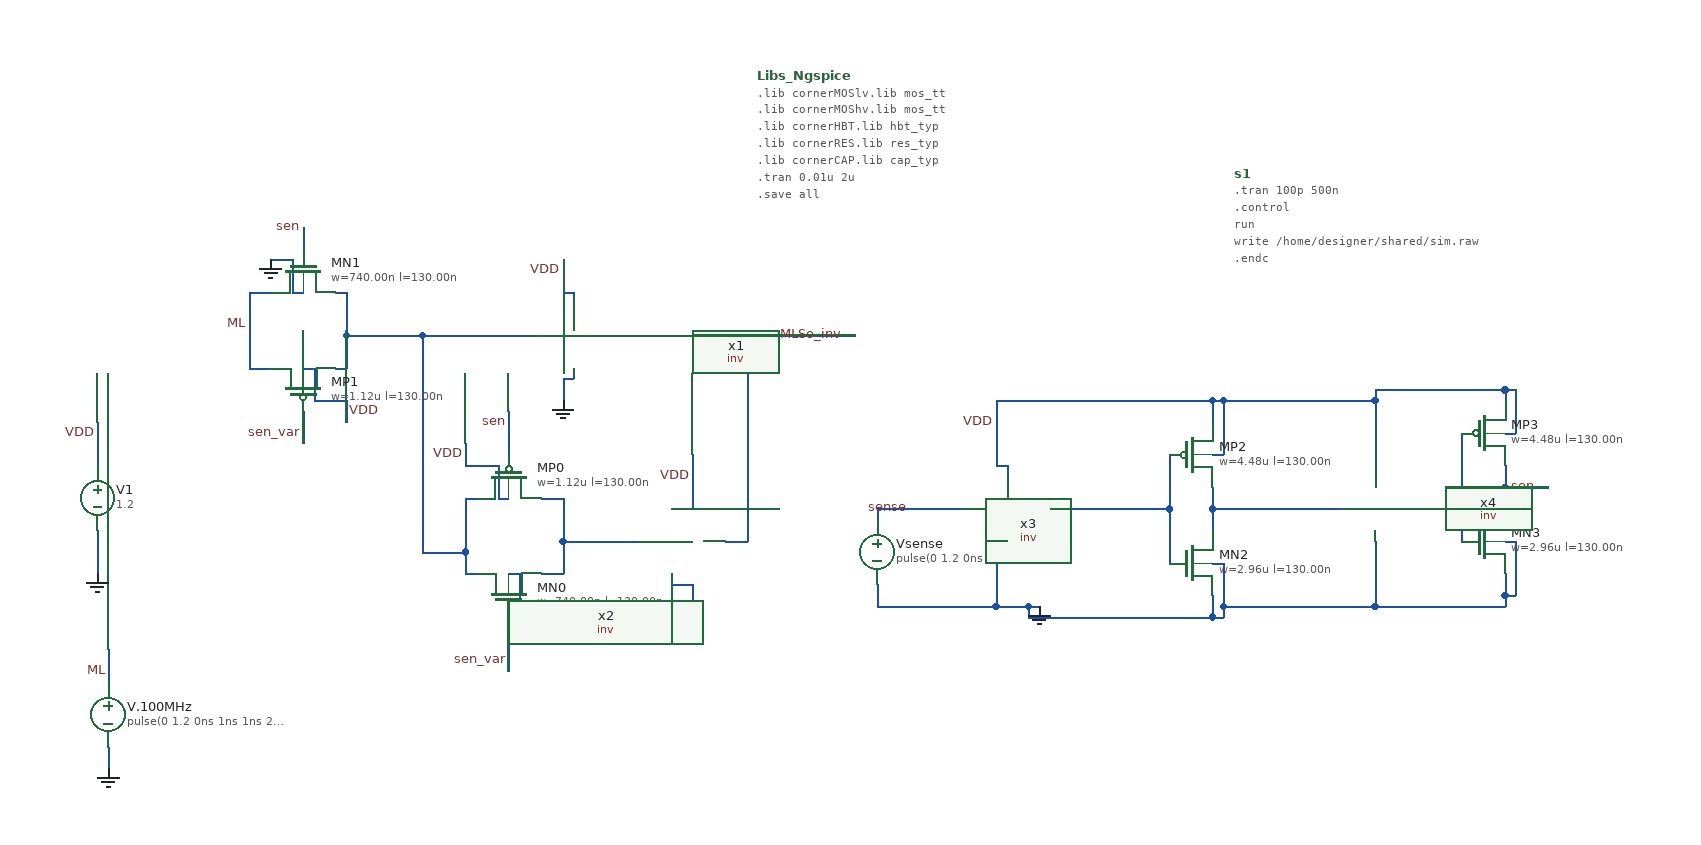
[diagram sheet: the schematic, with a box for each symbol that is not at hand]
v {xschem version=3.4.6 file_version=1.2}
G {}
K {}
V {}
S {}
E {}
N 460 -160 480 -160 {lab=#net1}
N 460 -90 480 -90 {lab=#net1}
N 390 -160 400 -160 {lab=#net2}
N 390 -110 390 -90 {lab=#net2}
N 390 -90 400 -90 {lab=#net2}
N 430 -90 440 -90 {lab=GND}
N 440 -90 440 -60 {lab=GND}
N 440 -60 460 -60 {lab=GND}
N 420 -160 430 -160 {lab=VDD}
N 420 -190 420 -160 {lab=VDD}
N 390 -190 420 -190 {lab=VDD}
N 390 -210 390 -190 {lab=VDD}
N 350 -310 450 -310 {lab=#net2}
N 480 -120 480 -90 {lab=#net1}
N 530 -310 650 -310 {lab=MLSo_inv}
N 650 -310 650 -120 {lab=MLSo_inv}
N 630 -120 650 -120 {lab=MLSo_inv}
N 350 -310 350 -110 {lab=#net2}
N 480 -380 480 -350 {lab=VDD}
N 600 -200 600 -150 {lab=VDD}
N 430 -240 430 -200 {lab=sen}
N 430 -50 430 0 {lab=sen_var}
N 480 -270 480 -250 {lab=GND}
N 600 -80 600 -60 {lab=GND}
N 50 -130 50 -90 {lab=GND}
N 50 -230 50 -190 {lab=VDD}
N 910 -60 920 -60 {lab=GND}
N 770 -150 770 -140 {lab=sense}
N 770 -150 850 -150 {lab=sense}
N 770 -80 770 -60 {lab=GND}
N 770 -60 880 -60 {lab=GND}
N 190 -280 210 -280 {lab=ML}
N 190 -350 210 -350 {lab=ML}
N 270 -280 280 -280 {lab=#net2}
N 270 -350 280 -350 {lab=#net2}
N 230 -350 240 -350 {lab=GND}
N 210 -380 230 -380 {lab=GND}
N 240 -280 250 -280 {lab=VDD}
N 250 -250 280 -250 {lab=VDD}
N 230 -380 230 -350 {lab=GND}
N 250 -280 250 -250 {lab=VDD}
N 280 -250 280 -230 {lab=VDD}
N 240 -410 240 -390 {lab=sen}
N 280 -310 280 -280 {lab=#net2}
N 190 -350 190 -280 {lab=ML}
N 240 -240 240 -210 {lab=sen_var}
N 930 -150 1040 -150 {lab=sen_var}
N 1080 -250 1090 -250 {lab=VDD}
N 1080 -200 1090 -200 {lab=VDD}
N 1080 -100 1090 -100 {lab=GND}
N 1080 -50 1090 -50 {lab=GND}
N 1040 -150 1040 -100 {lab=sen_var}
N 1080 -250 1080 -230 {lab=VDD}
N 1090 -250 1090 -200 {lab=VDD}
N 1090 -60 1090 -50 {lab=GND}
N 1080 -70 1080 -50 {lab=GND}
N 1040 -200 1040 -150 {lab=sen_var}
N 910 -50 1080 -50 {lab=GND}
N 910 -60 910 -50 {lab=GND}
N 880 -60 910 -60 {lab=GND}
N 880 -250 880 -190 {lab=VDD}
N 880 -250 1080 -250 {lab=VDD}
N 60 -20 60 10 {lab=ML}
N 60 70 60 90 {lab=GND}
N 650 -310 750 -310 {lab=MLSo_inv}
N 280 -310 350 -310 {lab=#net2}
N 280 -350 280 -310 {lab=#net2}
N 480 -120 550 -120 {lab=#net1}
N 480 -160 480 -120 {lab=#net1}
N 350 -110 390 -110 {lab=#net2}
N 390 -160 390 -110 {lab=#net2}
N 1230 -250 1230 -180 {lab=VDD}
N 1090 -250 1230 -250 {lab=VDD}
N 1090 -60 1230 -60 {lab=GND}
N 1090 -100 1090 -60 {lab=GND}
N 1350 -70 1350 -60 {lab=GND}
N 1230 -60 1350 -60 {lab=GND}
N 1350 -120 1360 -120 {lab=GND}
N 1360 -120 1360 -70 {lab=GND}
N 1350 -70 1360 -70 {lab=GND}
N 1350 -90 1350 -70 {lab=GND}
N 1230 -260 1230 -250 {lab=VDD}
N 1230 -260 1350 -260 {lab=VDD}
N 1350 -260 1350 -250 {lab=VDD}
N 1350 -220 1360 -220 {lab=VDD}
N 1360 -260 1360 -220 {lab=VDD}
N 1350 -260 1360 -260 {lab=VDD}
N 1350 -170 1350 -150 {lab=sen}
N 1080 -150 1080 -130 {lab=#net3}
N 1080 -150 1200 -150 {lab=#net3}
N 1080 -170 1080 -150 {lab=#net3}
N 1310 -150 1310 -120 {lab=#net4}
N 1280 -150 1310 -150 {lab=#net4}
N 1310 -220 1310 -150 {lab=#net4}
N 1350 -170 1390 -170 {lab=sen}
N 1350 -190 1350 -170 {lab=sen}
N 480 -270 490 -270 {lab=GND}
N 490 -280 490 -270 {lab=GND}
N 480 -350 490 -350 {lab=VDD}
N 490 -350 490 -340 {lab=VDD}
N 580 -150 600 -150 {lab=VDD}
N 580 -80 600 -80 {lab=GND}
N 580 -90 580 -80 {lab=GND}
N 890 -190 890 -180 {lab=VDD}
N 880 -190 890 -190 {lab=VDD}
N 880 -120 880 -60 {lab=GND}
N 880 -120 890 -120 {lab=GND}
N 1230 -120 1230 -60 {lab=GND}
C {/home/designer/shared/inv.sym} 530 -220 0 0 {name=x1}
C {sg13g2_pr/sg13_lv_pmos.sym} 430 -180 1 0 {name=MP0
l=130.00n
w=1.12u
ng=1
m=1
model=sg13_lv_pmos
spiceprefix=X
}
C {sg13g2_pr/sg13_lv_nmos.sym} 430 -70 3 0 {name=MN0
l=130.00n
w=740.00n
ng=1
m=1
model=sg13_lv_nmos
spiceprefix=X
}
C {gnd.sym} 460 -60 0 0 {name=l1 lab=GND}
C {lab_wire.sym} 390 -200 0 0 {name=p1 sig_type=std_logic lab=VDD
}
C {sg13g2_pr/sg13_lv_pmos.sym} 240 -260 3 0 {name=MP1
l=130.00n
w=1.12u
ng=1
m=1
model=sg13_lv_pmos
spiceprefix=X
}
C {sg13g2_pr/sg13_lv_nmos.sym} 240 -370 1 0 {name=MN1
l=130.00n
w=740.00n
ng=1
m=1
model=sg13_lv_nmos
spiceprefix=X
}
C {gnd.sym} 210 -380 2 0 {name=l2 lab=GND}
C {lab_wire.sym} 280 -240 2 0 {name=p2 sig_type=std_logic lab=VDD
}
C {gnd.sym} 480 -250 0 0 {name=l3 lab=GND}
C {gnd.sym} 600 -60 0 0 {name=l4 lab=GND}
C {lab_wire.sym} 600 -180 0 0 {name=p3 sig_type=std_logic lab=VDD}
C {lab_pin.sym} 480 -370 0 0 {name=p4 sig_type=std_logic lab=VDD}
C {vsource.sym} 50 -160 0 0 {name=V1 value=1.2 savecurrent=false}
C {gnd.sym} 50 -90 0 0 {name=l5 lab=GND}
C {lab_wire.sym} 50 -220 0 0 {name=p5 sig_type=std_logic lab=VDD}
C {lab_pin.sym} 950 -150 3 0 {name=p10 sig_type=std_logic lab=sen_var
}
C {gnd.sym} 920 -60 3 0 {name=l7 lab=GND}
C {lab_wire.sym} 880 -230 3 0 {name=p11 sig_type=std_logic lab=VDD}
C {vsource.sym} 770 -110 0 0 {name=Vsense value="pulse(0 1.2 0ns 1ns 1ns 125ns 250ns)" }
C {lab_wire.sym} 430 -10 0 0 {name=p9 sig_type=std_logic lab=sen_var}
C {lab_wire.sym} 240 -220 0 0 {name=p8 sig_type=std_logic lab=sen_var}
C {lab_wire.sym} 430 -230 0 0 {name=p13 sig_type=std_logic lab=sen}
C {lab_wire.sym} 240 -410 0 0 {name=p14 sig_type=std_logic lab=sen}
C {simulator_commands_shown.sym} 660 -550 0 0 {name=Libs_Ngspice
simulator=ngspice
only_toplevel=false
value="
.lib cornerMOSlv.lib mos_tt
.lib cornerMOShv.lib mos_tt
.lib cornerHBT.lib hbt_typ
.lib cornerRES.lib res_typ
.lib cornerCAP.lib cap_typ
.tran 0.01u 2u
.save all
"}
C {sg13g2_pr/sg13_lv_nmos.sym} 1060 -100 0 0 {name=MN2
l=130.00n
w=2.96u
ng=1
m=1
model=sg13_lv_nmos
spiceprefix=X
}
C {sg13g2_pr/sg13_lv_pmos.sym} 1060 -200 0 0 {name=MP2
l=130.00n
w=4.48u
ng=1
m=1
model=sg13_lv_pmos
spiceprefix=X
}
C {code.sym} 1100 -460 0 0 {name=s1 only_toplevel=false value=".tran 100p 500n
.control
run
write /home/designer/shared/sim.raw
.endc"}
C {vsource.sym} 60 40 0 0 {name=V.100MHz value="pulse(0 1.2 0ns 1ns 1ns 250ns 500ns)" }
C {gnd.sym} 60 90 0 0 {name=l6 lab=GND}
C {lab_wire.sym} 60 0 0 0 {name=p7 sig_type=std_logic lab=ML}
C {lab_pin.sym} 740 -310 0 0 {name=p15 sig_type=std_logic lab=MLSo_inv}
C {lab_wire.sym} 190 -320 0 0 {name=p12 sig_type=std_logic lab=ML}
C {lab_wire.sym} 800 -150 0 0 {name=p16 sig_type=std_logic lab=sense}
C {sg13g2_pr/sg13_lv_pmos.sym} 1330 -220 0 0 {name=MP3
l=130.00n
w=4.48u
ng=1
m=1
model=sg13_lv_pmos
spiceprefix=X
}
C {sg13g2_pr/sg13_lv_nmos.sym} 1330 -120 0 0 {name=MN3
l=130.00n
w=2.96u
ng=1
m=1
model=sg13_lv_nmos
spiceprefix=X
}
C {lab_wire.sym} 1380 -170 0 0 {name=p6 sig_type=std_logic lab=sen}
C {/home/designer/shared/inv.sym} 620 -30 0 0 {name=x2}
C {/home/designer/shared/inv.sym} 930 -60 0 0 {name=x3}
C {/home/designer/shared/inv.sym} 1270 -60 0 0 {name=x4}
